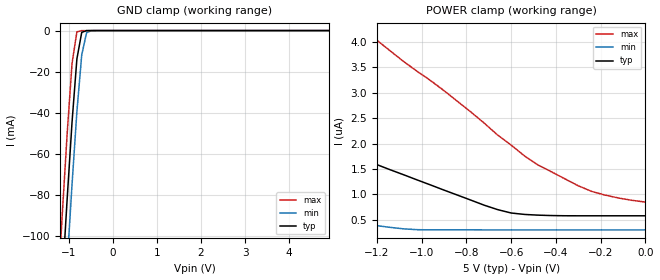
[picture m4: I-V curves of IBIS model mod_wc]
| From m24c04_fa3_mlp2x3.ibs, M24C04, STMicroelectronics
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|   Model mod_wc
[Model]   mod_wc
Model_type Input
Vinl   =   1.500V
Vinh   =   3.500V
C_comp   1.763pF   1.683pF   1.933pF
[Temperature Range]   25.0000   85.0000   -40.0000
[Voltage Range]   5.0000V   4.5000V   5.5000V
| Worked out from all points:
|   GND clamp passes 1 mA (typ) near -0.71 V on its own axis
[GND_clamp]
|Voltage   I(typ)   I(min)   I(max)
-5V       -1.63A     -1.659A    -1.601A
-1.26V    -162.1mA   -194mA     -129.6mA
-1.15V    -121.4mA   -153.3mA   -88.92mA
-1.04V    -81.84mA   -113.4mA   -50.02mA
-930mV    -44.68mA   -75mA      -16.05mA
-820mV    -13.86mA   -39.64mA   -620.3uA
-710mV    -876.1uA   -11.9mA    -4.426uA
-600mV    -18.76uA   -1.022mA   -29.45nA
-490mV    -372.8nA   -42.05uA   -196.9pA
4.9V      10.41pA    50.62pA    10.07pA
[POWER_clamp]
|Voltage   I(typ)   I(min)   I(max)
-4.98V    12.45uA    7.203uA    21.47uA
-3.72V    8.366uA    4.165uA    15.85uA
-3V       5.494uA    2.333uA    11.78uA
-2.7V     4.341uA    1.863uA    9.96uA
-2.64V    4.135uA    1.802uA    9.592uA
-2.4V     3.515uA    1.554uA    8.135uA
-1.26V    1.686uA    431.5nA    4.231uA
-1.02V    1.285uA    307.4nA    3.42uA
-660mV    701.2nA    303.3nA    2.166uA
-480mV    593.2nA    303.2nA    1.579uA
-240mV    580.5nA    303.2nA    1.06uA
0V        580.5nA    303.1nA    850.3nA
